VERSION 5.7 ;
  NOWIREEXTENSIONATPIN ON ;
  DIVIDERCHAR "/" ;
  BUSBITCHARS "[]" ;
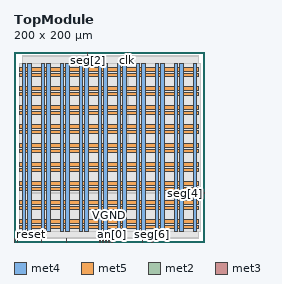
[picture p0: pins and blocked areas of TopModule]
MACRO TopModule
  CLASS BLOCK ;
  FOREIGN TopModule ;
  ORIGIN 0.000 0.000 ;
  SIZE 200.000 BY 200.000 ;
  PIN VGND
    DIRECTION INOUT ;
    USE GROUND ;
    PORT
      LAYER met4 ;
        RECT 14.220 10.640 18.220 187.920 ;
    END
    PORT
      LAYER met4 ;
        RECT 34.220 10.640 38.220 187.920 ;
    END
    PORT
      LAYER met4 ;
        RECT 54.220 10.640 58.220 187.920 ;
    END
    PORT
      LAYER met4 ;
        RECT 74.220 10.640 78.220 187.920 ;
    END
    PORT
      LAYER met4 ;
        RECT 94.220 10.640 98.220 187.920 ;
    END
    PORT
      LAYER met4 ;
        RECT 114.220 10.640 118.220 187.920 ;
    END
    PORT
      LAYER met4 ;
        RECT 134.220 10.640 138.220 187.920 ;
    END
    PORT
      LAYER met4 ;
        RECT 154.220 10.640 158.220 187.920 ;
    END
    PORT
      LAYER met4 ;
        RECT 174.220 10.640 178.220 187.920 ;
    END
    PORT
      LAYER met5 ;
        RECT 5.280 19.580 194.360 23.580 ;
    END
    PORT
      LAYER met5 ;
        RECT 5.280 39.580 194.360 43.580 ;
    END
    PORT
      LAYER met5 ;
        RECT 5.280 59.580 194.360 63.580 ;
    END
    PORT
      LAYER met5 ;
        RECT 5.280 79.580 194.360 83.580 ;
    END
    PORT
      LAYER met5 ;
        RECT 5.280 99.580 194.360 103.580 ;
    END
    PORT
      LAYER met5 ;
        RECT 5.280 119.580 194.360 123.580 ;
    END
    PORT
      LAYER met5 ;
        RECT 5.280 139.580 194.360 143.580 ;
    END
    PORT
      LAYER met5 ;
        RECT 5.280 159.580 194.360 163.580 ;
    END
    PORT
      LAYER met5 ;
        RECT 5.280 179.580 194.360 183.580 ;
    END
  END VGND
  PIN VPWR
    DIRECTION INOUT ;
    USE POWER ;
    PORT
      LAYER met4 ;
        RECT 8.520 10.640 12.520 187.920 ;
    END
    PORT
      LAYER met4 ;
        RECT 28.520 10.640 32.520 187.920 ;
    END
    PORT
      LAYER met4 ;
        RECT 48.520 10.640 52.520 187.920 ;
    END
    PORT
      LAYER met4 ;
        RECT 68.520 10.640 72.520 187.920 ;
    END
    PORT
      LAYER met4 ;
        RECT 88.520 10.640 92.520 187.920 ;
    END
    PORT
      LAYER met4 ;
        RECT 108.520 10.640 112.520 187.920 ;
    END
    PORT
      LAYER met4 ;
        RECT 128.520 10.640 132.520 187.920 ;
    END
    PORT
      LAYER met4 ;
        RECT 148.520 10.640 152.520 187.920 ;
    END
    PORT
      LAYER met4 ;
        RECT 168.520 10.640 172.520 187.920 ;
    END
    PORT
      LAYER met4 ;
        RECT 188.520 10.640 192.520 187.920 ;
    END
    PORT
      LAYER met5 ;
        RECT 5.280 13.880 194.360 17.880 ;
    END
    PORT
      LAYER met5 ;
        RECT 5.280 33.880 194.360 37.880 ;
    END
    PORT
      LAYER met5 ;
        RECT 5.280 53.880 194.360 57.880 ;
    END
    PORT
      LAYER met5 ;
        RECT 5.280 73.880 194.360 77.880 ;
    END
    PORT
      LAYER met5 ;
        RECT 5.280 93.880 194.360 97.880 ;
    END
    PORT
      LAYER met5 ;
        RECT 5.280 113.880 194.360 117.880 ;
    END
    PORT
      LAYER met5 ;
        RECT 5.280 133.880 194.360 137.880 ;
    END
    PORT
      LAYER met5 ;
        RECT 5.280 153.880 194.360 157.880 ;
    END
    PORT
      LAYER met5 ;
        RECT 5.280 173.880 194.360 177.880 ;
    END
  END VPWR
  PIN an[0]
    DIRECTION OUTPUT ;
    USE SIGNAL ;
    ANTENNADIFFAREA 0.445500 ;
    PORT
      LAYER met2 ;
        RECT 103.130 0.000 103.410 4.000 ;
    END
  END an[0]
  PIN an[1]
    DIRECTION OUTPUT ;
    USE SIGNAL ;
    ANTENNADIFFAREA 0.445500 ;
    PORT
      LAYER met2 ;
        RECT 96.690 0.000 96.970 4.000 ;
    END
  END an[1]
  PIN an[2]
    DIRECTION OUTPUT ;
    USE SIGNAL ;
    ANTENNADIFFAREA 0.445500 ;
    PORT
      LAYER met2 ;
        RECT 99.910 0.000 100.190 4.000 ;
    END
  END an[2]
  PIN an[3]
    DIRECTION OUTPUT ;
    USE SIGNAL ;
    ANTENNADIFFAREA 0.445500 ;
    PORT
      LAYER met2 ;
        RECT 90.250 0.000 90.530 4.000 ;
    END
  END an[3]
  PIN clk
    DIRECTION INPUT ;
    USE SIGNAL ;
    ANTENNAGATEAREA 0.852000 ;
    PORT
      LAYER met2 ;
        RECT 119.230 196.000 119.510 200.000 ;
    END
  END clk
  PIN control
    DIRECTION INPUT ;
    USE SIGNAL ;
    PORT
      LAYER met2 ;
        RECT 0.090 0.000 0.370 4.000 ;
    END
  END control
  PIN reset
    DIRECTION INPUT ;
    USE SIGNAL ;
    PORT
      LAYER met2 ;
        RECT 3.310 0.000 3.590 4.000 ;
    END
  END reset
  PIN seg[0]
    DIRECTION OUTPUT ;
    USE SIGNAL ;
    PORT
      LAYER met2 ;
        RECT 135.330 0.000 135.610 4.000 ;
    END
  END seg[0]
  PIN seg[1]
    DIRECTION OUTPUT ;
    USE SIGNAL ;
    PORT
      LAYER met2 ;
        RECT 29.070 0.000 29.350 4.000 ;
    END
  END seg[1]
  PIN seg[2]
    DIRECTION OUTPUT ;
    USE SIGNAL ;
    PORT
      LAYER met2 ;
        RECT 77.370 196.000 77.650 200.000 ;
    END
  END seg[2]
  PIN seg[3]
    DIRECTION OUTPUT ;
    USE SIGNAL ;
    PORT
      LAYER met2 ;
        RECT 93.470 0.000 93.750 4.000 ;
    END
  END seg[3]
  PIN seg[4]
    DIRECTION OUTPUT ;
    USE SIGNAL ;
    PORT
      LAYER met3 ;
        RECT 196.000 51.040 200.000 51.640 ;
    END
  END seg[4]
  PIN seg[5]
    DIRECTION OUTPUT ;
    USE SIGNAL ;
    PORT
      LAYER met2 ;
        RECT 54.830 0.000 55.110 4.000 ;
    END
  END seg[5]
  PIN seg[6]
    DIRECTION OUTPUT ;
    USE SIGNAL ;
    PORT
      LAYER met2 ;
        RECT 144.990 0.000 145.270 4.000 ;
    END
  END seg[6]
  OBS
      LAYER nwell ;
        RECT 5.330 10.795 194.310 187.870 ;
      LAYER li1 ;
        RECT 5.520 10.795 194.120 187.765 ;
      LAYER met1 ;
        RECT 5.520 10.640 194.510 187.920 ;
      LAYER met2 ;
        RECT 8.580 195.720 77.090 196.000 ;
        RECT 77.930 195.720 118.950 196.000 ;
        RECT 119.790 195.720 194.490 196.000 ;
        RECT 8.580 4.280 194.490 195.720 ;
        RECT 8.580 3.670 28.790 4.280 ;
        RECT 29.630 3.670 54.550 4.280 ;
        RECT 55.390 3.670 89.970 4.280 ;
        RECT 90.810 3.670 93.190 4.280 ;
        RECT 94.030 3.670 96.410 4.280 ;
        RECT 97.250 3.670 99.630 4.280 ;
        RECT 100.470 3.670 102.850 4.280 ;
        RECT 103.690 3.670 135.050 4.280 ;
        RECT 135.890 3.670 144.710 4.280 ;
        RECT 145.550 3.670 194.490 4.280 ;
      LAYER met3 ;
        RECT 8.530 52.040 196.000 187.845 ;
        RECT 8.530 50.640 195.600 52.040 ;
        RECT 8.530 10.715 196.000 50.640 ;
      LAYER met4 ;
        RECT 119.895 102.175 120.225 173.225 ;
  END
END TopModule
END LIBRARY

